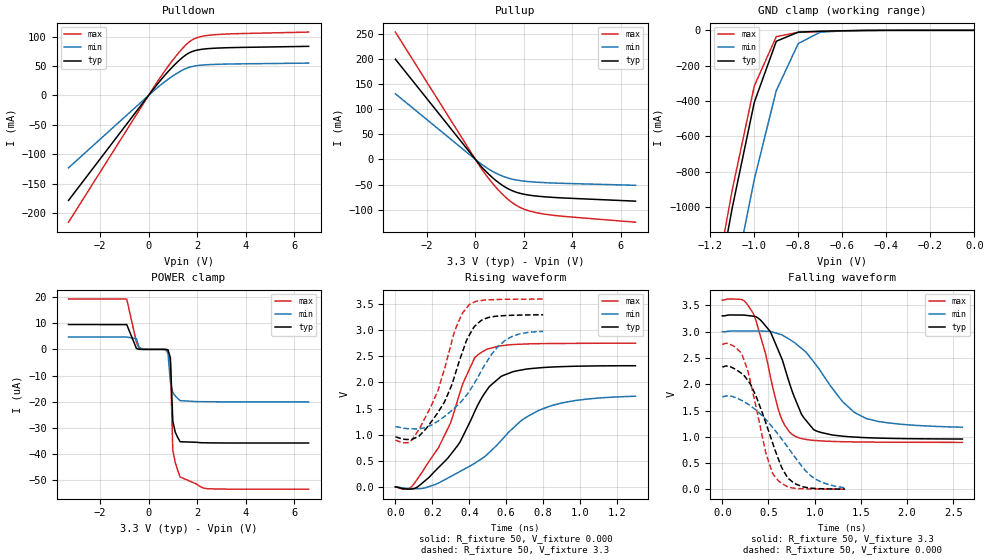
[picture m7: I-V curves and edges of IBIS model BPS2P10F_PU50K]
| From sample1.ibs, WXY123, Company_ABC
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|   Model BPS2P10F_PU50K
[Model]   BPS2P10F_PU50K
Model_type   I/O
Polarity   Non-Inverting
Enable   Active-High
Vinl   = 0.8V
Vinh   = 2V
Vmeas   = 1.65V
Cref   = 1.0pF
Vref   = 0V
Rref   = 1Mohms
C_comp   1.309pF NA   NA
[Temperature Range]   25   125   0
[Voltage Range]   3.3V   3.0V   3.6V
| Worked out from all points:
|   slope of the pulldown table from 0 to 0.495 V, typ, clamps not added: 19.2 ohm
|   slope of the pullup table from 0 to 0.495 V, typ, clamps not added: 18.4 ohm
|   GND clamp passes 1 mA (typ) near -0.52 V on its own axis
|   rising waveform, R_fixture 50, V_fixture 0.000: 20-80 % time 236ps typ, 360ps min, 200ps max; typ from 0 V to 2.32 V
|   rising waveform, R_fixture 50, V_fixture 3.3: 20-80 % time 159ps typ, 216ps min, 152ps max; typ from 0.954 V to 3.29 V
|   falling waveform, R_fixture 50, V_fixture 3.3: 20-80 % time 297ps typ, 490ps min, 233ps max; typ from 3.3 V to 0.958 V
|   falling waveform, R_fixture 50, V_fixture 0.000: 20-80 % time 290ps typ, 470ps min, 214ps max; typ from 2.33 V to 0.006 V
[Pulldown]
| voltage   I(typ)   I(min)   I(max)
-3.3V     -178.2mA   -122.9mA   -215.2mA
400mV     20.99mA    14.39mA    25.45mA
800mV     40.17mA    27.26mA    49.03mA
1.2V      57.1mA     38.28mA    70.31mA
1.5V      67.68mA    44.91mA    84.18mA
1.7V      72.79mA    48.04mA    91.54mA
1.9V      75.91mA    49.97mA    96.44mA
2.1V      77.71mA    51.1mA     99.32mA
2.7V      80.08mA    52.64mA    103mA
6.6V      83.32mA    54.84mA    107.5mA
[Pullup]
| voltage   I(typ)   I(min)   I(max)
-3.3V     200mA      131mA      254.1mA
300mV     -17.36mA   -11.2mA    -22.23mA
900mV     -44.22mA   -28.6mA    -58.61mA
1.4V      -59.79mA   -37.84mA   -81.84mA
1.7V      -65.69mA   -41.16mA   -91.99mA
2V        -69.41mA   -43.25mA   -99.1mA
2.7V      -73.92mA   -45.9mA    -108mA
3.7V      -77.04mA   -47.8mA    -113.9mA
6.6V      -83.23mA   -51.58mA   -125.2mA
[GND Clamp]
|  voltage   I(typ)   I(min)   I(max)
-3.3V     -17.71A    -17.93A    -17.8A
-1.2V     -1.683A    -2.14A     -1.588A
-1.1V     -1.004A    -1.466A    -902.4mA
-1V       -407.9mA   -843.5mA   -315mA
-900mV    -62.01mA   -341.1mA   -35.61mA
-800mV    -10.01mA   -74.36mA   -11.32mA
-700mV    -5.22mA    -10.57mA   -6.768mA
-500mV    -590.3uA   -1.149mA   -849.1uA
0V        0A         0A         0A
[POWER Clamp]
|  voltage   I(typ)   I(min)   I(max)
-3.3V     9.534uA    4.748uA    19.3uA
-900mV    9.525uA    4.743uA    19.28uA
-500mV    383.3nA    4.093uA    2.734uA
-400mV    64.96nA    1.028uA    554.3nA
700mV     -945.5pA   -38.37nA   1.119nA
800mV     -128.3nA   -1.426uA   -234.6nA
900mV     -3.244uA   -12.51uA   -5.353uA
1V        -27.42uA   -16.6uA    -38.74uA
1.1V      -31.68uA   -17.78uA   -43.3uA
1.3V      -35.35uA   -19.61uA   -48.83uA
2.4V      -35.77uA   -20.02uA   -53.31uA
6.6V      -35.84uA   -20.1uA    -53.52uA
| variable   typ   min   max
[Ramp]
dV/dt_r  1.39171V/0.235808ns   1.04175V/0.360119ns   1.65095V/0.200199ns
dV/dt_f  1.40503V/0.296571ns   1.09062V/0.489877ns   1.6233V/0.232586ns
R_load   = 50
[Rising Waveform]
R_fixture   = 50
V_fixture   = 0.000
V_fixture_min   = 0.000
V_fixture_max   = 0.000
| time   V(typ)   V(min)   V(max)
0s        481.1uV    348.5uV    624.3uV
91ps      -39.94mV   -32.25mV   16.71mV
234ps     373.4mV    75.61mV    756.7mV
299ps     619.9mV    198.3mV    1.229V
364ps     959.9mV    323.6mV    1.969V
429ps     1.441V     451.8mV    2.47V
468ps     1.709V     542.2mV    2.581V
572ps     2.115V     886.2mV    2.702V
780ps     2.28V      1.471V     2.743V
1.3ns     2.32V      1.737V     2.752V
[Rising Waveform]
R_fixture   = 50
V_fixture   = 3.3
V_fixture_min   = 3.0
V_fixture_max   = 3.6
| time   V(typ)   V(min)   V(max)
0s        953.5mV    1.15V      892.9mV
88ps      908.4mV    1.113V     894.5mV
128ps     971.7mV    1.116V     1.104V
224ps     1.392V     1.245V     1.792V
272ps     1.675V     1.366V     2.335V
328ps     2.207V     1.535V     3.046V
400ps     2.904V     1.829V     3.49V
464ps     3.186V     2.213V     3.569V
592ps     3.28V      2.8V       3.591V
800ps     3.295V     2.978V     3.596V
[Falling Waveform]
R_fixture   = 50
V_fixture   = 3.3
V_fixture_min   = 3.0
V_fixture_max   = 3.6
| time   V(typ)   V(min)   V(max)
0s        3.3V       3V         3.6V
208ps     3.316V     3.013V     3.612V
338ps     3.294V     3.013V     3.34V
520ps     3.001V     3.005V     2.155V
624ps     2.573V     2.951V     1.425V
780ps     1.759V     2.795V     1.022V
988ps     1.14V      2.43V      933mV
1.3ns     1.014V     1.675V     907.7mV
1.534ns   985.9mV    1.37V      901.3mV
2.6ns     958.3mV    1.182V     894.5mV
[Falling Waveform]
R_fixture   = 50
V_fixture   = 0.000
V_fixture_min   = 0.000
V_fixture_max   = 0.000
| time   V(typ)   V(min)   V(max)
0s        2.335V     1.767V     2.763V
212.8ps   2.201V     1.691V     2.565V
279.3ps   2.064V     1.621V     2.234V
478.8ps   1.226V     1.315V     653.3mV
545.3ps   883.5mV    1.179V     307.6mV
598.5ps   621.5mV    1.062V     183.9mV
704.9ps   229.5mV    812.4mV    52.59mV
798ps     101.4mV    588mV      20.96mV
1.024ns   16.25mV    182.4mV    7.616mV
1.33ns    6.211mV    31.54mV    5.095mV
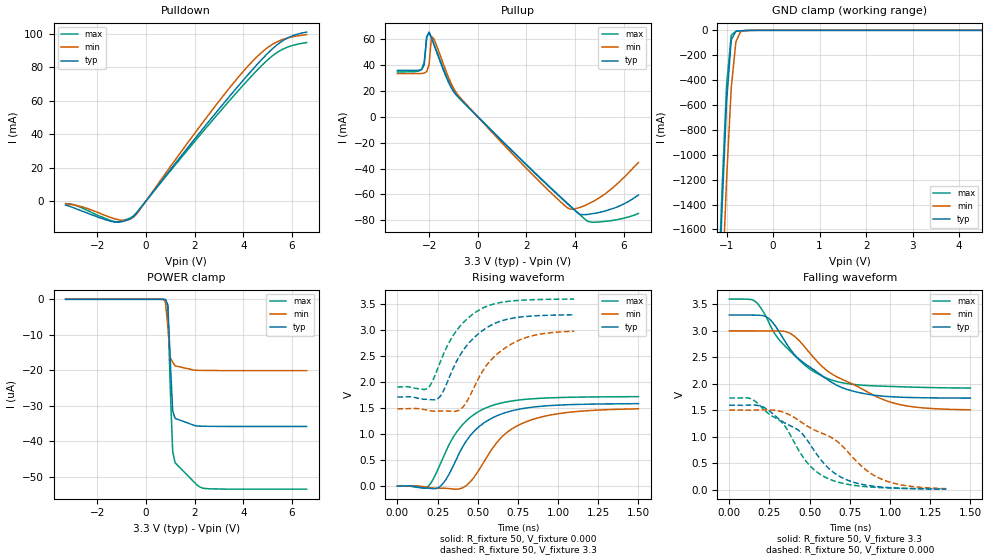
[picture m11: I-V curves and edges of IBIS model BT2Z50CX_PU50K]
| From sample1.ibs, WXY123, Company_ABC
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|   Model BT2Z50CX_PU50K
[Model]   BT2Z50CX_PU50K
Model_type   I/O
Polarity   Non-Inverting
Enable   Active-High
Vinl   = 0.8V
Vinh   = 2.0V
Vmeas   = 1.65V
Cref   = 1.0pF
Vref   = 0V
Rref   = 1Mohms
C_comp   1.26pF  NA   NA
[Temperature Range]   25   125   0
[Voltage Range]   3.3V   3.0V   3.6V
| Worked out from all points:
|   slope of the pulldown table from 0 to 0.495 V, typ, clamps not added: 53.3 ohm
|   slope of the pullup table from 0 to 0.495 V, typ, clamps not added: 52.7 ohm
|   GND clamp passes 1 mA (typ) near -0.54 V on its own axis
|   rising waveform, R_fixture 50, V_fixture 0.000: 20-80 % time 229ps typ, 260ps min, 222ps max; typ from 0.001 V to 1.58 V
|   rising waveform, R_fixture 50, V_fixture 3.3: 20-80 % time 210ps typ, 223ps min, 202ps max; typ from 1.71 V to 3.29 V
|   falling waveform, R_fixture 50, V_fixture 3.3: 20-80 % time 319ps typ, 416ps min, 284ps max; typ from 3.3 V to 1.73 V
|   falling waveform, R_fixture 50, V_fixture 0.000: 20-80 % time 313ps typ, 394ps min, 268ps max; typ from 1.6 V to 0.015 V
[Pulldown]
| voltage   I(typ)   I(min)   I(max)
-3.3V     -2.4mA     -1.6mA     -1.5mA
-2.6V     -6.1mA     -3.5mA     -4.3mA
-1.3V     -12.5mA    -10.5mA    -12.2mA
-800mV    -11.51mA   -11.45mA   -10.97mA
-500mV    -9.075mA   -9.476mA   -8.684mA
2.6V      47.85mA    52.05mA    45.93mA
3.6V      65.43mA    70.57mA    62.78mA
4.3V      77.25mA    82.31mA    74.07mA
4.9V      86.76mA    90.57mA    83mA
5.5V      94.6mA     95.89mA    89.78mA
6V        98.6mA     98.08mA    92.87mA
6.6V      101mA      99.42mA    94.71mA
[Pullup]
| voltage   I(typ)   I(min)   I(max)
-3.3V     35.95mA    33.42mA    34.77mA
-2.3V     36.63mA    33.57mA    37.02mA
-2.2V     40.28mA    33.87mA    42.51mA
-2.1V     61.88mA    34.91mA    61.35mA
-2V       65.55mA    40.4mA     65.33mA
-1.9V     60.89mA    62.22mA    61.01mA
-1.3V     30.92mA    35.23mA    32.21mA
-900mV    17.31mA    19.13mA    17.49mA
3.8V      -69.14mA   -71.33mA   -68.89mA
4.2V      -75.33mA   -69.94mA   -75.73mA
4.7V      -74.89mA   -65.74mA   -81.44mA
6.6V      -60.38mA   -35.24mA   -74.65mA
[GND Clamp]
|  voltage   I(typ)   I(min)   I(max)
-3.3V     -26.2A     -26.68A    -26.15A
-1.2V     -2.457A    -3.123A    -2.307A
-1.1V     -1.452A    -2.119A    -1.3A
-1V       -574.7mA   -1.197A    -440mA
-900mV    -76.61mA   -463mA     -38.79mA
-800mV    -7.355mA   -92.56mA   -7.94mA
-700mV    -3.454mA   -10.35mA   -4.753mA
-500mV    -491uA     -890.6uA   -717.6uA
6.6V      0A         0A         0A
[POWER Clamp]
|  voltage   I(typ)   I(min)   I(max)
-3.3V     3.749nA    82.59nA    19.09nA
600mV     2.038nA    51.33nA    7.354nA
700mV     1.194nA    12.62nA    5.685nA
800mV     -43.68nA   -679.6nA   -63.95nA
900mV     -1.442uA   -7.626uA   -2.028uA
1V        -17.1uA    -16.45uA   -24.88uA
1.1V      -31.45uA   -17.73uA   -42.94uA
1.2V      -33.57uA   -18.74uA   -46.08uA
2.1V      -35.69uA   -20uA      -52.34uA
2.3V      -35.76uA   -20.02uA   -53.16uA
2.6V      -35.79uA   -20.04uA   -53.4uA
6.6V      -35.84uA   -20.1uA    -53.52uA
| variable   typ   min   max
[Ramp]
dV/dt_r  0.950146V/0.229176ns   0.891184V/0.260292ns   1.0311V/0.221583ns
dV/dt_f  0.94062V/0.319408ns   0.89298V/0.416034ns   1.00716V/0.284201ns
R_load   = 50
[Rising Waveform]
R_fixture   = 50
V_fixture   = 0.000
V_fixture_min   = 0.000
V_fixture_max   = 0.000
| time   V(typ)   V(min)   V(max)
0s        923.3uV    493.9uV    1.406mV
180ps     -38.04mV   -19.08mV   -29.97mV
255ps     -30.73mV   -40.4mV    344mV
345ps     373.5mV    -56.07mV   931mV
420ps     829.3mV    -7.778mV   1.229V
570ps     1.277V     624.4mV    1.527V
690ps     1.429V     1.052V     1.625V
855ps     1.522V     1.294V     1.682V
1.095ns   1.568V     1.427V     1.709V
1.5ns     1.585V     1.486V     1.72V
[Rising Waveform]
R_fixture   = 50
V_fixture   = 3.3
V_fixture_min   = 3.0
V_fixture_max   = 3.6
| time   V(typ)   V(min)   V(max)
0s        1.712V     1.487V     1.907V
187ps     1.668V     1.458V     1.878V
253ps     1.685V     1.442V     2.28V
319ps     2.063V     1.442V     2.748V
396ps     2.549V     1.487V     3.097V
429ps     2.693V     1.611V     3.201V
528ps     2.986V     2.2V       3.418V
627ps     3.155V     2.556V     3.521V
759ps     3.248V     2.808V     3.571V
1.1ns     3.293V     2.979V     3.596V
[Falling Waveform]
R_fixture   = 50
V_fixture   = 3.3
V_fixture_min   = 3.0
V_fixture_max   = 3.6
| time   V(typ)   V(min)   V(max)
0s        3.3V       3V         3.6V
165ps     3.296V     3V         3.547V
255ps     3.21V      2.997V     3.102V
300ps     3.03V      2.998V     2.873V
375ps     2.672V     2.96V      2.629V
495ps     2.33V      2.604V     2.294V
615ps     2.073V     2.234V     2.097V
780ps     1.856V     1.978V     1.988V
1.035ns   1.754V     1.629V     1.949V
1.5ns     1.732V     1.512V     1.921V
[Falling Waveform]
R_fixture   = 50
V_fixture   = 0.000
V_fixture_min   = 0.000
V_fixture_max   = 0.000
| time   V(typ)   V(min)   V(max)
0s        1.598V     1.507V     1.734V
135ps     1.602V     1.506V     1.72V
243ps     1.506V     1.51V      1.442V
337.5ps   1.277V     1.464V     1.237V
432ps     1.123V     1.312V     746mV
513ps     811.1mV    1.156V     421.7mV
621ps     399.8mV    1.012V     206mV
756ps     161.7mV    654.9mV    96mV
945ps     54.95mV    206.6mV    43.52mV
1.35ns    14.88mV    24.09mV    19.1mV
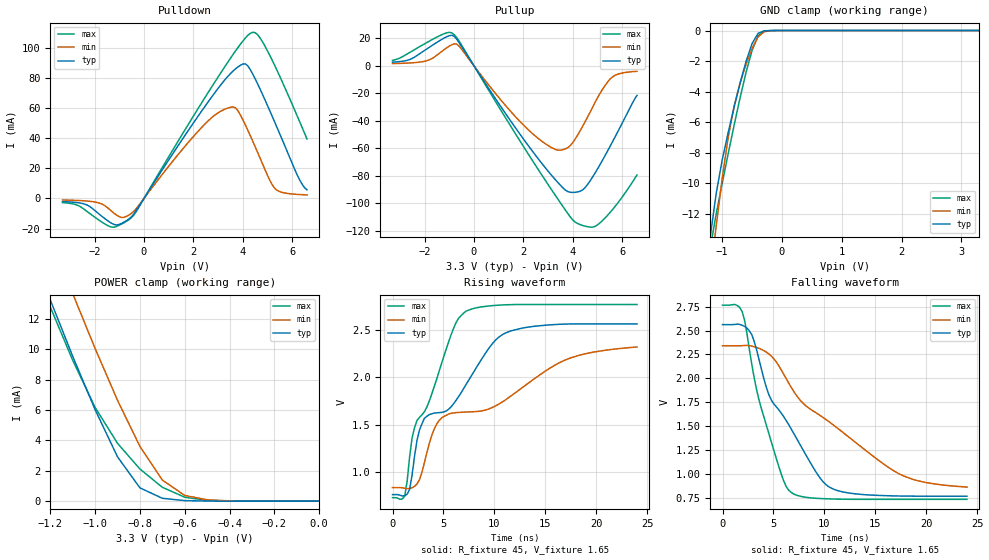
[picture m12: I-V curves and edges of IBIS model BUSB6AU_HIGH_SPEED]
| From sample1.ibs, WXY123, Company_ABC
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|   Model BUSB6AU_HIGH_SPEED
[Model]   BUSB6AU_HIGH_SPEED
Model_type   I/O
Polarity   Non-Inverting
Enable   Active-Low
Vinl   = 0.8V
Vinh   = 2.0V
Vmeas   = 1.65V
Cref   = 50pF
Vref   = 0V
Rref   = 1Mohms
C_comp   8.08pF  NA   NA
[Temperature Range]   25   125   0
[Voltage Range]   3.3V   3.0V   3.6V
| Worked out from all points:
|   slope of the pulldown table from 0 to 0.495 V, typ, clamps not added: 38.9 ohm
|   slope of the pullup table from 0 to 0.495 V, typ, clamps not added: 36.2 ohm
|   GND clamp passes 1 mA (typ) near -0.51 V on its own axis
|   POWER clamp passes 1 mA (typ) near -0.81 V on its own axis
|   rising waveform, R_fixture 45, V_fixture 1.65: 20-80 % time 6.71ns typ, 11.2ns min, 3.81ns max; typ from 0.766 V to 2.56 V
|   falling waveform, R_fixture 45, V_fixture 1.65: 20-80 % time 5.01ns typ, 9.13ns min, 2.79ns max; typ from 2.56 V to 0.766 V
[Pulldown]
| voltage   I(typ)   I(min)   I(max)
-3.3V     -2.11mA    -1.06mA    -2.781mA
-2.3V     -4.423mA   -1.76mA    -8.724mA
-1.3V     -16.61mA   -8.648mA   -19.08mA
-900mV    -16.52mA   -12.65mA   -16.95mA
-500mV    -12.07mA   -9.789mA   -12.64mA
2.8V      68.63mA    54.42mA    75.48mA
3.6V      84.45mA    60.73mA    95.38mA
4.1V      89.33mA    48.9mA     106.3mA
4.6V      76.03mA    30.56mA    108.7mA
5.3V      50.39mA    6.604mA    87.99mA
6.2V      15.69mA    2.671mA    54.87mA
6.6V      5.66mA     2.328mA    39.44mA
[Pullup]
| voltage   I(typ)   I(min)   I(max)
-3.3V     2.691mA    1.669mA    4.013mA
-2.6V     4.614mA    2.116mA    9.766mA
-1.9V     12.44mA    3.791mA    17.05mA
-1.1V     21.23mA    13.18mA    24.07mA
-800mV    21.5mA     15.99mA    22.66mA
2.4V      -62.85mA   -49.76mA   -69.78mA
3.3V      -82.89mA   -60.81mA   -94.33mA
3.9V      -91.91mA   -57.96mA   -109.9mA
4.4V      -90.19mA   -43.91mA   -116.1mA
5V        -75mA      -23.25mA   -115.6mA
5.6V      -55.51mA   -8.102mA   -104.7mA
6.6V      -21.47mA   -3.961mA   -79.36mA
[GND Clamp]
|  voltage   I(typ)   I(min)   I(max)
-3.3V     -94.63mA   -97.02mA   -94.31mA
-1.2V     -13.48mA   -16.12mA   -14.21mA
-1.1V     -10.65mA   -12.77mA   -12mA
-1V       -8.474mA   -9.671mA   -9.999mA
-900mV    -6.672mA   -6.992mA   -8.063mA
-800mV    -4.998mA   -4.936mA   -6.183mA
-600mV    -2.002mA   -2.192mA   -2.717mA
-500mV    -850.3uA   -1.159mA   -1.295mA
-400mV    -185.5uA   -418.7uA   -350.7uA
-300mV    -16.77uA   -80.31uA   -38.75uA
-200mV    -816.3nA   -8.857uA   -2.326uA
3.3V      1.775nA    1.608uA    6.149nA
[POWER Clamp]
|  voltage   I(typ)   I(min)   I(max)
-3.3V     97.08mA    100.8mA    96.36mA
-1.3V     17.06mA    21.19mA    16.49mA
-1.2V     13.25mA    17.39mA    12.79mA
-1.1V     9.541mA    13.67mA    9.278mA
-1V       6.024mA    10.05mA    6.173mA
-900mV    2.918mA    6.64mA     3.808mA
-800mV    874.5uA    3.605mA    2.118mA
-700mV    187.8uA    1.388mA    910.3uA
-600mV    32.94uA    375.7uA    257.2uA
-500mV    4.825uA    86.56uA    49.37uA
-400mV    624.4nA    18.32uA    7.577uA
0V        1.775nA    19.41nA    1.257nA
| variable   typ   min   max
[Ramp]
dV/dt_r  1.07779V/6.71285ns   0.888012V/11.2243ns   1.21929V/3.80873ns
dV/dt_f  1.0778V/5.0125ns   0.887595V/9.12738ns   1.21929V/2.78732ns
R_load   = 50
[Rising Waveform]
R_fixture   = 45
V_fixture   = 1.65
V_fixture_min   = 1.65
V_fixture_max   = 1.65
| time   V(typ)   V(min)   V(max)
0s        766.4mV    839.5mV    733.9mV
1.2ns     754.3mV    832.1mV    751.3mV
1.92ns    969.6mV    838.2mV    1.361V
2.4ns     1.335V     877.8mV    1.545V
3.12ns    1.568V     1.099V     1.637V
4.56ns    1.628V     1.543V     2.059V
7.2ns     1.921V     1.635V     2.695V
11.52ns   2.485V     1.796V     2.764V
17.28ns   2.561V     2.196V     2.766V
24ns      2.563V     2.32V      2.766V
[Falling Waveform]
R_fixture   = 45
V_fixture   = 1.65
V_fixture_min   = 1.65
V_fixture_max   = 1.65
| time   V(typ)   V(min)   V(max)
0s        2.563V     2.341V     2.766V
1.92ns    2.557V     2.342V     2.701V
2.88ns    2.457V     2.338V     2.143V
3.6ns     2.19V      2.313V     1.767V
4.8ns     1.772V     2.232V     1.332V
6.72ns    1.474V     1.911V     808mV
9.6ns     954.5mV    1.61V      742.3mV
11.04ns   834.4mV    1.499V     736.7mV
17.76ns   768.1mV    979.6mV    733.9mV
24ns      766.4mV    862.2mV    733.9mV
